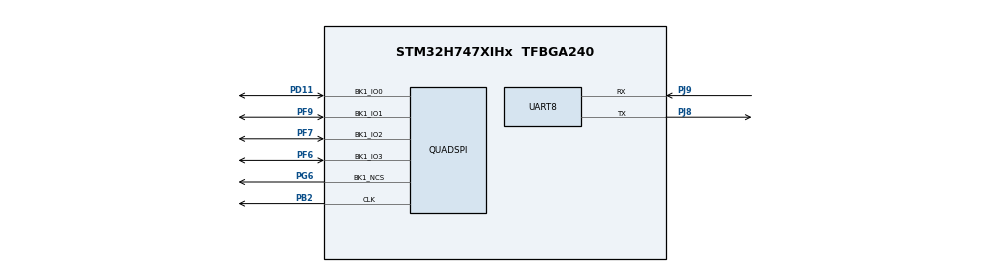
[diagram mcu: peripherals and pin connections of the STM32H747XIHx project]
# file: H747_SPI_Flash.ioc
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Mcu.Family=STM32H7
RCC.HSIDiv=RCC_PLLSAIDIVR_1
RCC.CortexFreq_Value=64000000
PJ9.Mode=Asynchronous
PG6.Signal=QUADSPI_BK1_NCS
RCC.PLLDSIIDF=DSI_PLL_IN_DIV1
PG6.Mode=Single Bank 1
ProjectManager.StackSize=0x400
RCC.DSIPHY_Div=8
PF7.Signal=QUADSPI_BK1_IO2
RCC.HCLKFreq_Value=64000000
RCC.RCC_RTC_Clock_Source_FROM_HSE=RCC_RTCCLKSOURCE_HSE_DIV2
PB2.Signal=QUADSPI_CLK
NVIC2.PriorityGroup=NVIC_PRIORITYGROUP_4
PF9.Mode=Single Bank 1
VP_SYS_M4_VS_Systick.Mode=SysTick
CortexM7.IPs=BDMA\:I,CORTEX_M7\:I,DEBUG\:I,DMA\:I,FATFS_M7\:I,FREERTOS_M7\:I,IWDG1\:I,MDMA\:I,NVIC1\:I,OPENAMP_M7\:I,PDM2PCM_M7\:I,PWR\:I,RCC\:I,RESMGR_UTILITY\:I,SYS\:I,USB_DEVICE_M7\:I,USB_HOST_M7\:I,VREFBUF\:I,WWDG1\:I,UART8\:I,QUADSPI\:I
PF7.PinAttribute=CortexM7
RCC.SAI23CLockSelection=RCC_SAI23CLKSOURCE_PLL
RCC.APB3Freq_Value=64000000
Mcu.Package=TFBGA240
PJ9.PinAttribute=CortexM7
PJ9.Signal=UART8_RX
RCC.APB4Freq_Value=64000000
RCC.PLLDSIDev=2
PJ8.Mode=Asynchronous
RCC.DSITX_Div=4
PF9.PinAttribute=CortexM7
NVIC1.PriorityGroup=NVIC_PRIORITYGROUP_4
RCC.D2PPRE1=RCC_APB1_DIV2
RCC.Cortex_DivARG=SystemCoreClock/1000
PJ8.PinAttribute=CortexM7
SYS.userName=SYS_M7
PB2.PinAttribute=CortexM7
PF7.Mode=Single Bank 1
PF6.Signal=QUADSPI_BK1_IO3
ProjectManager.TargetToolchain=STM32CubeIDE
NVIC1.QUADSPI_IRQn=true\:0\:0\:false\:false\:true\:true\:true
RCC.USBFreq_Value=129000000
board=custom
RCC.APB2Freq_Value=64000000
RCC.PLLDSINDIV=20
RCC.ADCFreq_Value=129000000
RCC.PLLDSIODF=DSI_PLL_OUT_DIV1
PD11.PinAttribute=CortexM7
RCC.PLLDSIMult=2
Mcu.Name=STM32H747XIHx
RCC.SYSCLKFreq_VALUE=64000000
PD11.Signal=QUADSPI_BK1_IO0
PB2.Mode=Single Bank 1
PG6.PinAttribute=CortexM7
PJ8.Signal=UART8_TX
ProjectManager.HeapSize=0x200
PD11.Mode=Single Bank 1
PF6.PinAttribute=CortexM7
PF6.Mode=Single Bank 1
PF9.Signal=QUADSPI_BK1_IO1
RCC.D3PPRE=RCC_APB4_DIV1
RCC.Cortex_Div=SYSTICK_CLKSOURCE_HCLK
RCC.DIVR3=2
RCC.APB1Freq_Value=32000000
RCC.DIVR2=2
RCC.DIVR1=2
CortexM4.IPs=BDMA,CORTEX_M4\:I,DEBUG,DMA,FATFS_M4\:I,FREERTOS_M4\:I,IWDG2\:I,MDMA,NVIC2\:I,OPENAMP_M4\:I,PDM2PCM_M4\:I,PWR,RCC,RESMGR_UTILITY,SYS_M4\:I,USB_DEVICE_M4\:I,USB_HOST_M4\:I,VREFBUF,WWDG2\:I

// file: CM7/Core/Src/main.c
/* USER CODE BEGIN Header */
/**
  ******************************************************************************
  * @file           : main.c
  * @brief          : Main program body
  ******************************************************************************
  * @attention
  *
  * <h2><center>&copy; Copyright (c) 2021 STMicroelectronics.
  * All rights reserved.</center></h2>
  *
  * This software component is licensed by ST under BSD 3-Clause license,
  * the "License"; You may not use this file except in compliance with the
  * License. You may obtain a copy of the License at:
  *                        opensource.org/licenses/BSD-3-Clause
  *
  ******************************************************************************
  */
/* USER CODE END Header */
#include <string.h>
#include <stdio.h>

#include "main.h"
#include "quadspi.h"

#ifndef HSEM_ID_0
#define HSEM_ID_0 (0U) /* HW semaphore 0*/
#endif

#define SECTORS_COUNT 100

QSPI_HandleTypeDef hqspi;
UART_HandleTypeDef huart8;

uint8_t aTxBuffer[SECTORS_COUNT] = {1,1,1,1,1,1,1,1,1,1};

void SystemClock_Config(void);
static void MX_GPIO_Init(void);
static void MX_UART8_Init(void);

int __io_putchar (int ch) {
	uint8_t c = ch;
	HAL_UART_Transmit(&huart8, &c, 1, HAL_MAX_DELAY);
	return ch;
}

int main(void)
{
	int32_t timeout;

	timeout = 0xFFFF;
	while((__HAL_RCC_GET_FLAG(RCC_FLAG_D2CKRDY) != RESET) && (timeout-- > 0));
	if ( timeout < 0 )
	{
		Error_Handler();
	}

	HAL_Init();

	SystemClock_Config();

	__HAL_RCC_HSEM_CLK_ENABLE();
	/*Take HSEM */
	HAL_HSEM_FastTake(HSEM_ID_0);
	/*Release HSEM in order to notify the CPU2(CM4)*/
	HAL_HSEM_Release(HSEM_ID_0,0);
	/* wait until CPU2 wakes up from stop mode */
	timeout = 0xFFFF;
	while((__HAL_RCC_GET_FLAG(RCC_FLAG_D2CKRDY) == RESET) && (timeout-- > 0));
	if ( timeout < 0 )
	{
		Error_Handler();
	}

	MX_GPIO_Init();
	MX_QUADSPI_Init();
	MX_UART8_Init();

	uint8_t buffer_test[MEMORY_SECTOR_SIZE];
    uint32_t var = 0;

    printf("OKKKKK\r\n");

  	//CSP_QUADSPI_Init();

  	if (CSP_QUADSPI_Init() == HAL_OK)
	{
  		printf("==Init Success==\r\n");
	}

  	for (var = 0; var < MEMORY_SECTOR_SIZE; var++) {
  		//buffer_test[var] = (var & 0xff);
  		buffer_test[var] = 15;
  	}

  	for (var = 0; var < SECTORS_COUNT; var++) {
  		if (CSP_QSPI_WriteMemory(buffer_test, var * MEMORY_SECTOR_SIZE, sizeof(buffer_test)) != HAL_OK) {
  			printf("==False 2==\r\n");
  			while (1);
  		}
  	}

  	if (CSP_QSPI_EnableMemoryMappedMode() != HAL_OK) {
  		printf("==False 3==\r\n");
  		while (1);
  	}

//  	for (var = 0; var < SECTORS_COUNT; var++) {
//  		if (memcmp(buffer_test, (uint8_t*)(0x90000000 + var * MEMORY_SECTOR_SIZE), MEMORY_SECTOR_SIZE) != HAL_OK) {
//  			printf("==False 4==\r\n");
//  			while (1);
//  		}
//  	}

  	for (var = 0; var < SECTORS_COUNT; var++) {
  			printf("==Value %d==\r\n",*(((uint8_t*)(0x90000000 + var * MEMORY_SECTOR_SIZE)) + var));
  	}

	while (1)
	{
		printf("DHCP IP\r\n");
		HAL_Delay(1000);
	}
}

///**
//  * @brief System Clock Configuration
//  * @retval None
//  */
//void SystemClock_Config(void)
//{
//  RCC_OscInitTypeDef RCC_OscInitStruct = {0};
//  RCC_ClkInitTypeDef RCC_ClkInitStruct = {0};
//
//  /** Supply configuration update enable
//  */
//  HAL_PWREx_ConfigSupply(PWR_LDO_SUPPLY);
//  /** Configure the main internal regulator output voltage
//  */
//  __HAL_PWR_VOLTAGESCALING_CONFIG(PWR_REGULATOR_VOLTAGE_SCALE3);
//
//  while(!__HAL_PWR_GET_FLAG(PWR_FLAG_VOSRDY)) {}
//  /** Initializes the RCC Oscillators according to the specified parameters
//  * in the RCC_OscInitTypeDef structure.
//  */
//  RCC_OscInitStruct.OscillatorType = RCC_OSCILLATORTYPE_HSI;
//  RCC_OscInitStruct.HSIState = RCC_HSI_DIV1;
//  RCC_OscInitStruct.HSICalibrationValue = RCC_HSICALIBRATION_DEFAULT;
//  RCC_OscInitStruct.PLL.PLLState = RCC_PLL_NONE;
//  if (HAL_RCC_OscConfig(&RCC_OscInitStruct) != HAL_OK)
//  {
//    Error_Handler();
//  }
//  /** Initializes the CPU, AHB and APB buses clocks
//  */
//  RCC_ClkInitStruct.ClockType = RCC_CLOCKTYPE_HCLK|RCC_CLOCKTYPE_SYSCLK
//                              |RCC_CLOCKTYPE_PCLK1|RCC_CLOCKTYPE_PCLK2
//                              |RCC_CLOCKTYPE_D3PCLK1|RCC_CLOCKTYPE_D1PCLK1;
//  RCC_ClkInitStruct.SYSCLKSource = RCC_SYSCLKSOURCE_HSI;
//  RCC_ClkInitStruct.SYSCLKDivider = RCC_SYSCLK_DIV1;
//  RCC_ClkInitStruct.AHBCLKDivider = RCC_HCLK_DIV1;
//  RCC_ClkInitStruct.APB3CLKDivider = RCC_APB3_DIV1;
//  RCC_ClkInitStruct.APB1CLKDivider = RCC_APB1_DIV2;
//  RCC_ClkInitStruct.APB2CLKDivider = RCC_APB2_DIV1;
//  RCC_ClkInitStruct.APB4CLKDivider = RCC_APB4_DIV1;
//
//  if (HAL_RCC_ClockConfig(&RCC_ClkInitStruct, FLASH_LATENCY_1) != HAL_OK)
//  {
//    Error_Handler();
//  }
//}

void SystemClock_Config(void)
{
  RCC_OscInitTypeDef RCC_OscInitStruct = {0};
  RCC_ClkInitTypeDef RCC_ClkInitStruct = {0};
  RCC_PeriphCLKInitTypeDef PeriphClkInitStruct = {0};

  /** Supply configuration update enable
  */
  HAL_PWREx_ConfigSupply(PWR_DIRECT_SMPS_SUPPLY);
  /** Configure the main internal regulator output voltage
  */
  __HAL_PWR_VOLTAGESCALING_CONFIG(PWR_REGULATOR_VOLTAGE_SCALE1);

  while(!__HAL_PWR_GET_FLAG(PWR_FLAG_VOSRDY)) {}
  /** Macro to configure the PLL clock source
  */
  __HAL_RCC_PLL_PLLSOURCE_CONFIG(RCC_PLLSOURCE_HSI);
  /** Initializes the RCC Oscillators according to the specified parameters
  * in the RCC_OscInitTypeDef structure.
  */
  RCC_OscInitStruct.OscillatorType = RCC_OSCILLATORTYPE_HSI|RCC_OSCILLATORTYPE_LSI;
  RCC_OscInitStruct.HSIState = RCC_HSI_DIV1;
  RCC_OscInitStruct.HSICalibrationValue = RCC_HSICALIBRATION_DEFAULT;
  RCC_OscInitStruct.LSIState = RCC_LSI_ON;
  RCC_OscInitStruct.PLL.PLLState = RCC_PLL_ON;
  RCC_OscInitStruct.PLL.PLLSource = RCC_PLLSOURCE_HSI;
  RCC_OscInitStruct.PLL.PLLM = 32;
  RCC_OscInitStruct.PLL.PLLN = 129;
  RCC_OscInitStruct.PLL.PLLP = 2;
  RCC_OscInitStruct.PLL.PLLQ = 2;
  RCC_OscInitStruct.PLL.PLLR = 2;
  RCC_OscInitStruct.PLL.PLLRGE = RCC_PLL1VCIRANGE_1;
  RCC_OscInitStruct.PLL.PLLVCOSEL = RCC_PLL1VCOWIDE;
  RCC_OscInitStruct.PLL.PLLFRACN = 0;
  if (HAL_RCC_OscConfig(&RCC_OscInitStruct) != HAL_OK)
  {
    Error_Handler();
  }
  /** Initializes the CPU, AHB and APB buses clocks
  */
  RCC_ClkInitStruct.ClockType = RCC_CLOCKTYPE_HCLK|RCC_CLOCKTYPE_SYSCLK
                              |RCC_CLOCKTYPE_PCLK1|RCC_CLOCKTYPE_PCLK2
                              |RCC_CLOCKTYPE_D3PCLK1|RCC_CLOCKTYPE_D1PCLK1;
  RCC_ClkInitStruct.SYSCLKSource = RCC_SYSCLKSOURCE_HSI;
  RCC_ClkInitStruct.SYSCLKDivider = RCC_SYSCLK_DIV1;
  RCC_ClkInitStruct.AHBCLKDivider = RCC_HCLK_DIV1;
  RCC_ClkInitStruct.APB3CLKDivider = RCC_APB3_DIV1;
  RCC_ClkInitStruct.APB1CLKDivider = RCC_APB1_DIV1;
  RCC_ClkInitStruct.APB2CLKDivider = RCC_APB2_DIV1;
  RCC_ClkInitStruct.APB4CLKDivider = RCC_APB4_DIV1;

  if (HAL_RCC_ClockConfig(&RCC_ClkInitStruct, FLASH_LATENCY_0) != HAL_OK)
  {
    Error_Handler();
  }
  PeriphClkInitStruct.PeriphClockSelection = RCC_PERIPHCLK_RTC|RCC_PERIPHCLK_USART1
                              |RCC_PERIPHCLK_UART8|RCC_PERIPHCLK_SPDIFRX
                              |RCC_PERIPHCLK_SPI5|RCC_PERIPHCLK_SPI2
                              |RCC_PERIPHCLK_SAI1|RCC_PERIPHCLK_SDMMC
                              |RCC_PERIPHCLK_ADC|RCC_PERIPHCLK_CEC
                              |RCC_PERIPHCLK_QSPI|RCC_PERIPHCLK_FMC;
  PeriphClkInitStruct.PLL2.PLL2M = 32;
  PeriphClkInitStruct.PLL2.PLL2N = 129;
  PeriphClkInitStruct.PLL2.PLL2P = 2;
  PeriphClkInitStruct.PLL2.PLL2Q = 2;
  PeriphClkInitStruct.PLL2.PLL2R = 2;
  PeriphClkInitStruct.PLL2.PLL2RGE = RCC_PLL2VCIRANGE_1;
  PeriphClkInitStruct.PLL2.PLL2VCOSEL = RCC_PLL2VCOWIDE;
  PeriphClkInitStruct.PLL2.PLL2FRACN = 0;
  PeriphClkInitStruct.FmcClockSelection = RCC_FMCCLKSOURCE_D1HCLK;
  PeriphClkInitStruct.QspiClockSelection = RCC_QSPICLKSOURCE_D1HCLK;
  PeriphClkInitStruct.SdmmcClockSelection = RCC_SDMMCCLKSOURCE_PLL;
  PeriphClkInitStruct.Sai1ClockSelection = RCC_SAI1CLKSOURCE_PLL;
  PeriphClkInitStruct.Spi123ClockSelection = RCC_SPI123CLKSOURCE_PLL;
  PeriphClkInitStruct.Spi45ClockSelection = RCC_SPI45CLKSOURCE_D2PCLK1;
  PeriphClkInitStruct.SpdifrxClockSelection = RCC_SPDIFRXCLKSOURCE_PLL;
  PeriphClkInitStruct.Usart234578ClockSelection = RCC_USART234578CLKSOURCE_D2PCLK1;
  PeriphClkInitStruct.Usart16ClockSelection = RCC_USART16CLKSOURCE_D2PCLK2;
  PeriphClkInitStruct.CecClockSelection = RCC_CECCLKSOURCE_LSI;
  PeriphClkInitStruct.AdcClockSelection = RCC_ADCCLKSOURCE_PLL2;
  PeriphClkInitStruct.RTCClockSelection = RCC_RTCCLKSOURCE_LSI;
  if (HAL_RCCEx_PeriphCLKConfig(&PeriphClkInitStruct) != HAL_OK)
  {
    Error_Handler();
  }
  HAL_RCC_MCOConfig(RCC_MCO1, RCC_MCO1SOURCE_HSI, RCC_MCODIV_1);
}

static void MX_UART8_Init(void)
{
  huart8.Instance = UART8;
  huart8.Init.BaudRate = 115200;
  huart8.Init.WordLength = UART_WORDLENGTH_8B;
  huart8.Init.StopBits = UART_STOPBITS_1;
  huart8.Init.Parity = UART_PARITY_NONE;
  huart8.Init.Mode = UART_MODE_TX_RX;
  huart8.Init.HwFlowCtl = UART_HWCONTROL_NONE;
  huart8.Init.OverSampling = UART_OVERSAMPLING_16;
  huart8.Init.OneBitSampling = UART_ONE_BIT_SAMPLE_DISABLE;
  huart8.Init.ClockPrescaler = UART_PRESCALER_DIV1;
  huart8.AdvancedInit.AdvFeatureInit = UART_ADVFEATURE_NO_INIT;
  if (HAL_UART_Init(&huart8) != HAL_OK)
  {
    Error_Handler();
  }
  if (HAL_UARTEx_SetTxFifoThreshold(&huart8, UART_TXFIFO_THRESHOLD_1_8) != HAL_OK)
  {
    Error_Handler();
  }
  if (HAL_UARTEx_SetRxFifoThreshold(&huart8, UART_RXFIFO_THRESHOLD_1_8) != HAL_OK)
  {
    Error_Handler();
  }
  if (HAL_UARTEx_DisableFifoMode(&huart8) != HAL_OK)
  {
    Error_Handler();
  }
}

static void MX_GPIO_Init(void)
{

  /* GPIO Ports Clock Enable */
  __HAL_RCC_GPIOG_CLK_ENABLE();
  __HAL_RCC_GPIOF_CLK_ENABLE();
  __HAL_RCC_GPIOJ_CLK_ENABLE();
  __HAL_RCC_GPIOB_CLK_ENABLE();
  __HAL_RCC_GPIOD_CLK_ENABLE();

}

void Error_Handler(void)
{

}

/************************ (C) COPYRIGHT STMicroelectronics *****END OF FILE****/
